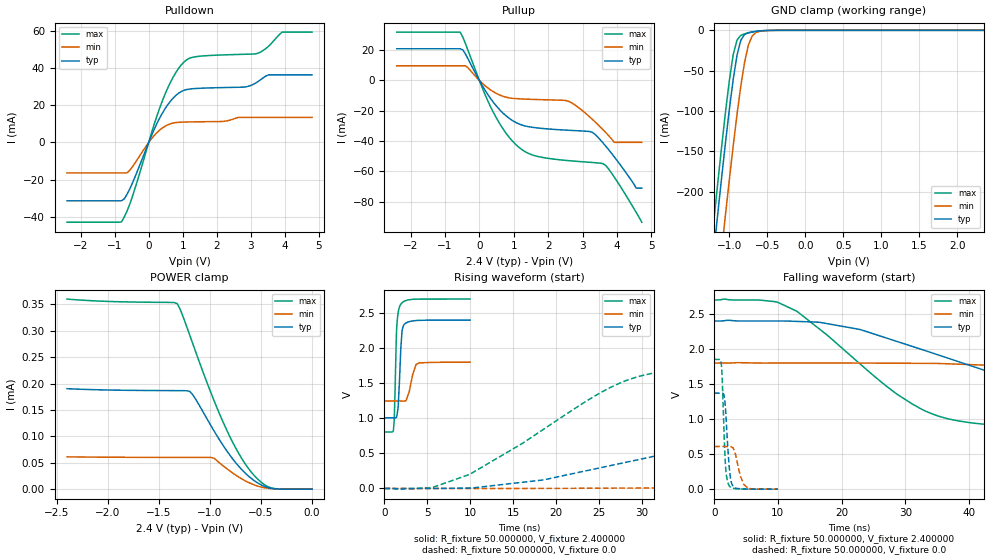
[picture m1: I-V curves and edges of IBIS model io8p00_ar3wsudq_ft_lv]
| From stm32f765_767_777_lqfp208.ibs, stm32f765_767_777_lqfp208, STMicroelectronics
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|   Model io8p00_ar3wsudq_ft_lv
[Model]  io8p00_ar3wsudq_ft_lv
Model_type I/O
Polarity   Non-Inverting
Enable   Active-Low
Vinl =   0.720000V
Vinh =   1.680000V
Vmeas =  1.200000V
Cref =   50.000000pF
Rref =   100.000000M
Vref =   0.0V
C_comp   3.740200pF   3.683500pF   3.822900pF
[Temperature Range]   25.000000   0.125000k   -40.000000
[Pullup Reference]   2.400000V   1.800000V   2.700000V
[Pulldown Reference]   0.0V   0.0V   0.0V
[POWER Clamp Reference]   2.400000V   1.800000V   2.700000V
[GND Clamp Reference]   0.0V   0.0V   0.0V
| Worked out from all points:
|   slope of the pulldown table from 0 to 0.36 V, typ, clamps not added: 25 ohm
|   slope of the pullup table from 0 to 0.36 V, typ, clamps not added: 27.7 ohm
|   GND clamp passes 1 mA (typ) near -0.62 V on its own axis
|   rising waveform, R_fixture 50.000000, V_fixture 2.400000: 20-80 % time 329ps typ, 643ps min, 256ps max; typ from 1.01 V to 2.4 V
|   rising waveform, R_fixture 50.000000, V_fixture 0.0: 20-80 % time 32.3ns typ, 81ns min, 14.8ns max; typ from 0 V to 1.37 V
|   falling waveform, R_fixture 50.000000, V_fixture 2.400000: 20-80 % time 29.1ns typ, 72.5ns min, 15.7ns max; typ from 2.4 V to 1.01 V
|   falling waveform, R_fixture 50.000000, V_fixture 0.0: 20-80 % time 594ps typ, 1.03ns min, 462ps max; typ from 1.37 V to 0 V
[Pulldown]
|Voltage   I(typ)   I(min)   I(max)
-2.4V     -31.47mA   -16.45mA   -43.01mA
-800mV    -31.47mA   -16.45mA   -42.85mA
-480mV    -21.98mA   -13.17mA   -29.21mA
80mV      3.63mA     1.966mA    5.014mA
480mV     18.16mA    8.738mA    26.02mA
800mV     25.38mA    10.72mA    37.77mA
1.12V     28.53mA    11.02mA    44.6mA
2.8V      29.84mA    13.51mA    47.53mA
3.2V      32.66mA    13.51mA    48.04mA
3.52V     36.44mA    13.51mA    51.84mA
3.92V     36.44mA    13.51mA    59.5mA
4.8V      36.44mA    13.51mA    59.5mA
[Pullup]
|Voltage   I(typ)   I(min)   I(max)
-2.4V     20.89mA    9.661mA    31.89mA
-560mV    20.89mA    9.661mA    31.89mA
-400mV    17.28mA    9.661mA    24.06mA
320mV     -11.75mA   -6.207mA   -17.08mA
960mV     -26.47mA   -11.82mA   -40.02mA
1.52V     -30.88mA   -12.51mA   -49.05mA
2.56V     -32.88mA   -13.52mA   -52.9mA
3.28V     -34.25mA   -25.63mA   -54.18mA
3.6V      -41.44mA   -32.74mA   -55.03mA
3.92V     -50.47mA   -40.9mA    -63.79mA
4.56V     -71.1mA    -40.9mA    -87.26mA
4.72V     -71.1mA    -40.9mA    -93.6mA
[GND_clamp]
|Voltage   I(typ)   I(min)   I(max)
-2.4V     -1.43A     -1.515A    -1.4A
-1.25V    -315.9mA   -407.2mA   -278.2mA
-1.2V     -270.1mA   -361.3mA   -232.1mA
-1.15V    -225mA     -316mA     -186.8mA
-1.1V     -180.9mA   -271.3mA   -142.7mA
-1.05V    -138.2mA   -227.5mA   -100.5mA
-950mV    -61.14mA   -143.6mA   -30.43mA
-900mV    -31.23mA   -104.7mA   -12.14mA
-850mV    -12.49mA   -69.4mA    -6.221mA
-750mV    -2.898mA   -18.35mA   -3.18mA
-600mV    -750.2uA   -1.218mA   -738.3uA
2.35V     0A         0A         0A
[POWER_clamp]
|Voltage   I(typ)   I(min)   I(max)
-2.4V     190.2uA    61.19uA    359.9uA
-1.32V    186.6uA    60.14uA    351.2uA
-1.29V    186.5uA    60.13uA    339.6uA
-1.2V     185.4uA    60.11uA    292.6uA
-1.17V    179.2uA    60.11uA    276.3uA
-960mV    110.2uA    58.62uA    167.5uA
-870mV    82.44uA    43.99uA    126.3uA
-750mV    50.58uA    26.92uA    78.64uA
-630mV    25.94uA    13.41uA    41.02uA
-510mV    9.22uA     4.527uA    14.97uA
-420mV    2.425uA    1.38uA     3.75uA
0V        0A         0A         0A
[Ramp]
| variable   typ   min   max
dV/dt_r  0.82206/32.24971n   0.36255/83.54246n   1.11078/14.74251n
dV/dt_f  0.83652/29.04373n   0.32640/73.61923n   1.13720/15.66467n
R_load = 50.000000
[Rising Waveform]
R_fixture= 50.000000
V_fixture= 2.400000
V_fixture_min= 1.800000
V_fixture_max= 2.700000
|time   V(typ)   V(min)   V(max)
0s        1.006V     1.247V     804.6mV
1.041ns   1.006V     1.247V     830.9mV
1.141ns   1.006V     1.247V     1.004V
1.421ns   1.019V     1.247V     2.284V
1.602ns   1.185V     1.247V     2.511V
1.882ns   1.947V     1.247V     2.624V
2.042ns   2.24V      1.246V     2.647V
2.182ns   2.315V     1.245V     2.66V
4.024ns   2.396V     1.79V      2.699V
9.97ns    2.4V       1.8V       2.7V
[Rising Waveform]
R_fixture= 50.000000
V_fixture= 0.0
V_fixture_min= 0.0
V_fixture_max= 0.0
|time   V(typ)   V(min)   V(max)
0s        6.447nV    361.2nV    2.755nV
5.506ns   -210.6uV   -120.4uV   13.13mV
9.51ns    5.653mV    -62.13uV   182.9mV
27.03ns   344.6mV    4.862mV    1.481V
32.53ns   492mV      9.434mV    1.676V
38.04ns   657.6mV    26.44mV    1.755V
64.06ns   1.222V     114.3mV    1.839V
79.08ns   1.313V     188.9mV    1.849V
148.1ns   1.368V     493mV      1.852V
249.2ns   1.37V      609.1mV    1.852V
[Falling Waveform]
R_fixture= 50.000000
V_fixture= 2.400000
V_fixture_min= 1.800000
V_fixture_max= 2.700000
|time   V(typ)   V(min)   V(max)
0s        2.4V       1.8V       2.7V
10.01ns   2.4V       1.8V       2.665V
13.01ns   2.394V     1.8V       2.536V
22.52ns   2.285V     1.8V       1.816V
31.53ns   2.024V     1.796V     1.192V
44.54ns   1.631V     1.763V     906.6mV
58.56ns   1.265V     1.718V     851.8mV
83.58ns   1.084V     1.58V      819.9mV
176.2ns   1.01V      1.276V     804.5mV
249.2ns   1.006V     1.247V     804.6mV
[Falling Waveform]
R_fixture= 50.000000
V_fixture= 0.0
V_fixture_min= 0.0
V_fixture_max= 0.0
|time   V(typ)   V(min)   V(max)
0s        1.37V      609.1mV    1.852V
1.141ns   1.37V      609.1mV    1.762V
1.722ns   1.207V     608.8mV    417.6mV
1.942ns   892.4mV    608.5mV    181.3mV
2.302ns   378.9mV    609.6mV    56.32mV
2.543ns   165.5mV    609.2mV    30.25mV
2.943ns   44.91mV    591.9mV    13.19mV
4.104ns   4.992mV    186.7mV    2.606mV
5.285ns   1.442mV    14.22mV    758.7uV
9.97ns    6.447nV    361.2nV    2.755nV
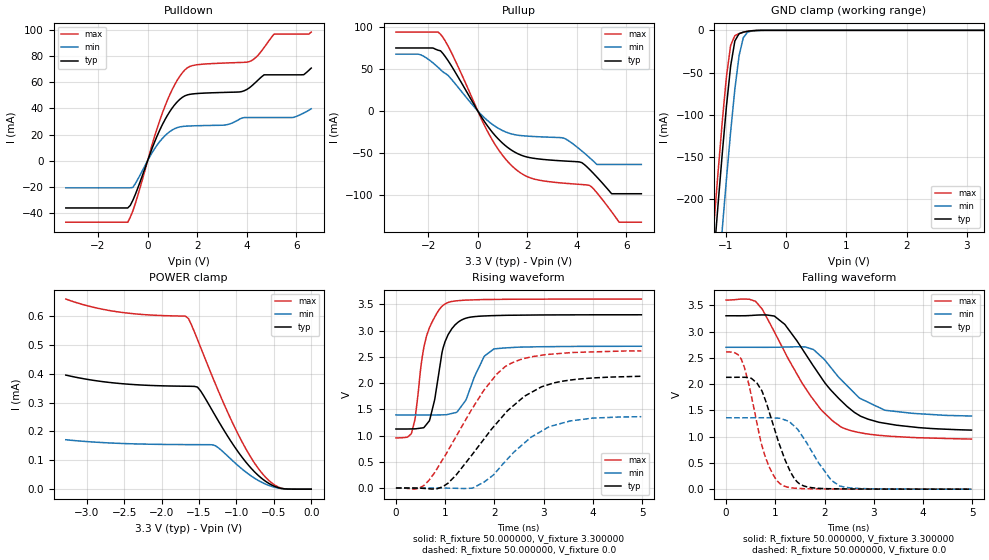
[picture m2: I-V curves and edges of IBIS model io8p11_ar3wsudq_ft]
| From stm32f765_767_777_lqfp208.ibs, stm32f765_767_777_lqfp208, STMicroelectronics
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|   Model io8p11_ar3wsudq_ft
[Model]  io8p11_ar3wsudq_ft
Model_type I/O
Polarity   Non-Inverting
Enable   Active-Low
Vinl =   0.990000V
Vinh =   2.310000V
Vmeas =  1.650000V
Cref =   30.000000pF
Rref =   100.000000M
Vref =   0.0V
C_comp   3.843200pF   3.761700pF   3.937000pF
[Temperature Range]   25.000000   0.125000k   -40.000000
[Pullup Reference]   3.300000V   2.700000V   3.600000V
[Pulldown Reference]   0.0V   0.0V   0.0V
[POWER Clamp Reference]   3.300000V   2.700000V   3.600000V
[GND Clamp Reference]   0.0V   0.0V   0.0V
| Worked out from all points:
|   slope of the pulldown table from 0 to 0.495 V, typ, clamps not added: 20.9 ohm
|   slope of the pullup table from 0 to 0.495 V, typ, clamps not added: 22.6 ohm
|   GND clamp passes 1 mA (typ) near -0.62 V on its own axis
|   rising waveform, R_fixture 50.000000, V_fixture 3.300000: 20-80 % time 279ps typ, 352ps min, 279ps max; typ from 1.12 V to 3.3 V
|   rising waveform, R_fixture 50.000000, V_fixture 0.0: 20-80 % time 1.18ns typ, 961ps min, 1.04ns max; typ from 0 V to 2.13 V
|   falling waveform, R_fixture 50.000000, V_fixture 3.300000: 20-80 % time 1.07ns typ, 865ps min, 1.02ns max; typ from 3.3 V to 1.12 V
|   falling waveform, R_fixture 50.000000, V_fixture 0.0: 20-80 % time 466ps typ, 565ps min, 398ps max; typ from 2.13 V to 0 V
[Pulldown]
|Voltage   I(typ)   I(min)   I(max)
-3.3V     -36.18mA   -20.77mA   -47.07mA
-800mV    -36.18mA   -20.77mA   -47.07mA
-600mV    -30.5mA    -20.52mA   -38.69mA
700mV     31.4mA     19.11mA    41.71mA
1.2V      45.15mA    25.37mA    61.75mA
1.6V      50.35mA    26.5mA     71.06mA
3.1V      52.28mA    27.26mA    74.76mA
4.1V      55.71mA    33.01mA    75.8mA
4.7V      65.73mA    33.01mA    86.69mA
5.1V      65.73mA    33.01mA    96.9mA
6.3V      65.85mA    36.5mA     96.9mA
6.6V      70.91mA    39.71mA    98.45mA
[Pullup]
|Voltage   I(typ)   I(min)   I(max)
-3.3V     74.74mA    67.41mA    93.61mA
-2.3V     74.74mA    66.57mA    93.61mA
-1.5V     71.37mA    49.01mA    91.04mA
500mV     -22.07mA   -14mA      -30.03mA
1.6V      -50.64mA   -28.81mA   -70.96mA
3.5V      -59.53mA   -32.72mA   -85.92mA
4.2V      -61.52mA   -47.62mA   -87.46mA
4.5V      -69.21mA   -55.27mA   -88.43mA
4.8V      -78.38mA   -63.6mA    -97.01mA
5.4V      -98.4mA    -63.6mA    -119.7mA
5.7V      -98.4mA    -63.6mA    -132.2mA
6.6V      -98.4mA    -63.6mA    -132.2mA
[GND_clamp]
|Voltage   I(typ)   I(min)   I(max)
-3.3V     -2.325A    -2.404A    -2.299A
-1.2V     -270.2mA   -361.4mA   -232.1mA
-1.13V    -207.3mA   -298.1mA   -169mA
-1.06V    -146.7mA   -236.2mA   -108.8mA
-990mV    -90.18mA   -176.4mA   -54.96mA
-920mV    -42.21mA   -120mA     -17.68mA
-850mV    -12.57mA   -69.47mA   -6.265mA
-780mV    -3.971mA   -30.01mA   -3.886mA
-710mV    -2.1mA     -8.615mA   -2.382mA
-640mV    -1.148mA   -2.283mA   -1.22mA
-570mV    -524uA     -821.5uA   -476.8uA
3.28V     0A         0A         0A
[POWER_clamp]
|Voltage   I(typ)   I(min)   I(max)
-3.28V    395.3uA    171.3uA    658.7uA
-2.6V     367.1uA    159uA      614.9uA
-1.68V    356.7uA    154.4uA    599.4uA
-1.64V    356.5uA    154.4uA    590.8uA
-1.52V    353.6uA    154.3uA    518.3uA
-1.48V    341.1uA    154.2uA    492.3uA
-1.28V    253.6uA    150.4uA    364.2uA
-960mV    123.1uA    77.56uA    181.6uA
-720mV    50.52uA    32.03uA    76.18uA
-560mV    18.94uA    12.27uA    28.65uA
-440mV    5.104uA    3.69uA     7.327uA
0V        0A         0A         0A
[Ramp]
| variable   typ   min   max
dV/dt_r  1.25880/1.16613n   0.80004/0.94614n   1.56012/1.04037n
dV/dt_f  1.27488/1.04977n   0.76812/0.84639n   1.56922/1.01475n
R_load = 50.000000
[Rising Waveform]
R_fixture= 50.000000
V_fixture= 3.300000
V_fixture_min= 2.700000
V_fixture_max= 3.600000
|time   V(typ)   V(min)   V(max)
0s        1.124V     1.392V     954.3mV
320.3ps   1.126V     1.392V     1.056V
390.4ps   1.127V     1.392V     1.324V
560.6ps   1.148V     1.392V     2.643V
680.7ps   1.281V     1.392V     3.052V
1.011ns   2.816V     1.395V     3.514V
1.421ns   3.235V     1.674V     3.579V
1.792ns   3.277V     2.505V     3.59V
1.992ns   3.284V     2.65V      3.592V
4.985ns   3.3V       2.7V       3.599V
[Rising Waveform]
R_fixture= 50.000000
V_fixture= 0.0
V_fixture_min= 0.0
V_fixture_max= 0.0
|time   V(typ)   V(min)   V(max)
0s        345.1uV    196.2uV    650.8uV
570.6ps   -7.291mV   186.7uV    49.81mV
1.061ns   94.14mV    -2.415mV   718.2mV
1.562ns   652.2mV    -576.7uV   1.531V
2.042ns   1.23V      314.7mV    2.163V
2.282ns   1.485V     568.7mV    2.348V
2.613ns   1.75V      860.9mV    2.468V
3.123ns   1.977V     1.172V     2.547V
3.994ns   2.096V     1.331V     2.593V
4.985ns   2.129V     1.359V     2.612V
[Falling Waveform]
R_fixture= 50.000000
V_fixture= 3.300000
V_fixture_min= 2.700000
V_fixture_max= 3.600000
|time   V(typ)   V(min)   V(max)
0s        3.3V       2.7V       3.599V
600.6ps   3.311V     2.7V       3.573V
740.7ps   3.316V     2.7V       3.416V
981ps     3.295V     2.701V     2.994V
1.201ns   3.126V     2.704V     2.594V
1.772ns   2.347V     2.659V     1.707V
2.342ns   1.678V     2.078V     1.18V
2.713ns   1.4V       1.732V     1.077V
3.223ns   1.255V     1.503V     1.015V
4.985ns   1.124V     1.392V     954.3mV
[Falling Waveform]
R_fixture= 50.000000
V_fixture= 0.0
V_fixture_min= 0.0
V_fixture_max= 0.0
|time   V(typ)   V(min)   V(max)
0s        2.129V     1.359V     2.612V
310.3ps   2.129V     1.359V     2.472V
470.5ps   2.117V     1.358V     1.966V
630.6ps   2.015V     1.358V     1.242V
880.9ps   1.457V     1.359V     415.9mV
1.131ns   729.4mV    1.338V     82.34mV
1.491ns   102.4mV    1.088V     13.53mV
2.132ns   8.311mV    175.9mV    3.479mV
2.312ns   5.515mV    59.99mV    3.074mV
4.985ns   345.1uV    196.2uV    650.8uV
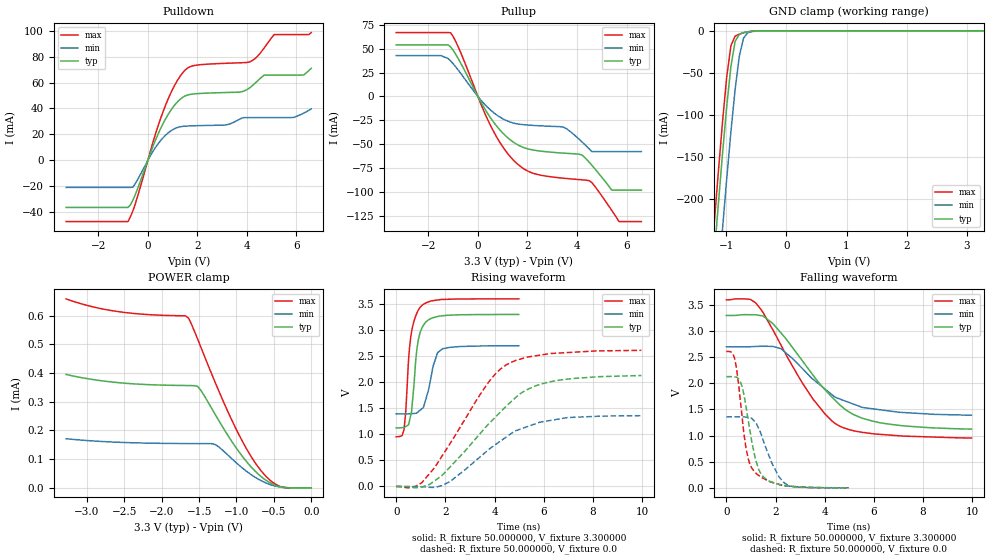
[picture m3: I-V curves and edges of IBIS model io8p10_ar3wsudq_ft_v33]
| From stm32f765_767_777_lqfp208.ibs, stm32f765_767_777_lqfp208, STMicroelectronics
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|   Model io8p10_ar3wsudq_ft_v33
[Model]  io8p10_ar3wsudq_ft_v33
Model_type I/O
Polarity   Non-Inverting
Enable   Active-Low
Vinl =   0.990000V
Vinh =   2.310000V
Vmeas =  1.650000V
Cref =   40.000000pF
Rref =   100.000000M
Vref =   0.0V
C_comp   3.857500pF   3.760500pF   3.941700pF
[Temperature Range]   25.000000   0.125000k   -40.000000
[Pullup Reference]   3.300000V   2.700000V   3.600000V
[Pulldown Reference]   0.0V   0.0V   0.0V
[POWER Clamp Reference]   3.300000V   2.700000V   3.600000V
[GND Clamp Reference]   0.0V   0.0V   0.0V
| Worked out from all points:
|   slope of the pulldown table from 0 to 0.495 V, typ, clamps not added: 20.9 ohm
|   slope of the pullup table from 0 to 0.495 V, typ, clamps not added: 22.6 ohm
|   GND clamp passes 1 mA (typ) near -0.62 V on its own axis
|   rising waveform, R_fixture 50.000000, V_fixture 3.300000: 20-80 % time 278ps typ, 400ps min, 275ps max; typ from 1.12 V to 3.3 V
|   rising waveform, R_fixture 50.000000, V_fixture 0.0: 20-80 % time 2.56ns typ, 2.3ns min, 2.13ns max; typ from 0 V to 2.13 V
|   falling waveform, R_fixture 50.000000, V_fixture 3.300000: 20-80 % time 2.28ns typ, 2.11ns min, 2.06ns max; typ from 3.3 V to 1.12 V
|   falling waveform, R_fixture 50.000000, V_fixture 0.0: 20-80 % time 516ps typ, 709ps min, 442ps max; typ from 2.13 V to 0 V
[Pulldown]
|Voltage   I(typ)   I(min)   I(max)
-3.3V     -36.18mA   -20.77mA   -47.07mA
-800mV    -36.18mA   -20.77mA   -47.07mA
-600mV    -30.5mA    -20.52mA   -38.69mA
700mV     31.4mA     19.11mA    41.71mA
1.2V      45.15mA    25.37mA    61.75mA
1.6V      50.35mA    26.5mA     71.06mA
3.1V      52.28mA    27.26mA    74.76mA
4.1V      55.7mA     32.99mA    75.8mA
4.7V      65.72mA    32.99mA    86.64mA
5.1V      65.72mA    32.99mA    96.89mA
6.3V      65.85mA    36.5mA     96.89mA
6.6V      70.91mA    39.71mA    98.45mA
[Pullup]
|Voltage   I(typ)   I(min)   I(max)
-3.3V     54.18mA    42.91mA    67.09mA
-1.5V     54.18mA    42.91mA    67.09mA
-1.1V     51.95mA    37.28mA    66.83mA
500mV     -22.07mA   -14mA      -30.03mA
1.5V      -49.1mA    -28.3mA    -68.56mA
2.2V      -56.05mA   -30.32mA   -80.35mA
3.5V      -59.53mA   -32.72mA   -85.92mA
4.2V      -61.52mA   -47.6mA    -87.46mA
4.5V      -69.21mA   -55.15mA   -88.43mA
5.4V      -98.3mA    -57.9mA    -119.4mA
5.7V      -98.3mA    -57.9mA    -131.3mA
6.6V      -98.3mA    -57.9mA    -131.3mA
[GND_clamp]
|Voltage   I(typ)   I(min)   I(max)
-3.3V     -2.333A    -2.407A    -2.313A
-1.2V     -270.2mA   -361.4mA   -232.1mA
-1.13V    -207.3mA   -298.1mA   -169mA
-1.06V    -146.7mA   -236.2mA   -108.8mA
-990mV    -90.18mA   -176.4mA   -54.96mA
-920mV    -42.21mA   -120mA     -17.68mA
-850mV    -12.57mA   -69.47mA   -6.265mA
-780mV    -3.971mA   -30.01mA   -3.886mA
-710mV    -2.1mA     -8.615mA   -2.382mA
-640mV    -1.148mA   -2.283mA   -1.22mA
-570mV    -524uA     -821.5uA   -476.8uA
3.28V     0A         0A         0A
[POWER_clamp]
|Voltage   I(typ)   I(min)   I(max)
-3.28V    395.3uA    171.3uA    658.7uA
-2.6V     367.1uA    159uA      614.9uA
-1.68V    356.7uA    154.4uA    599.4uA
-1.64V    356.5uA    154.4uA    590.8uA
-1.52V    353.6uA    154.3uA    518.3uA
-1.48V    341.1uA    154.2uA    492.3uA
-1.28V    253.6uA    150.4uA    364.2uA
-960mV    123.1uA    77.55uA    181.6uA
-720mV    50.52uA    32.03uA    76.18uA
-560mV    18.94uA    12.27uA    28.65uA
-440mV    5.104uA    3.69uA     7.327uA
0V        0A         0A         0A
[Ramp]
| variable   typ   min   max
dV/dt_r  1.26882/2.56042n   0.81306/2.31943n   1.56564/2.13181n
dV/dt_f  1.28502/2.27385n   0.77796/2.11306n   1.57580/2.05912n
R_load = 50.000000
[Rising Waveform]
R_fixture= 50.000000
V_fixture= 3.300000
V_fixture_min= 2.700000
V_fixture_max= 3.600000
|time   V(typ)   V(min)   V(max)
0s        1.124V     1.392V     954.2mV
320.3ps   1.132V     1.392V     1.098V
390.4ps   1.151V     1.391V     1.455V
510.5ps   1.199V     1.392V     2.477V
650.7ps   1.576V     1.398V     3.035V
830.8ps   2.593V     1.409V     3.315V
991ps     2.978V     1.471V     3.448V
1.682ns   3.26V      2.566V     3.577V
1.882ns   3.274V     2.641V     3.588V
4.985ns   3.3V       2.7V       3.599V
[Rising Waveform]
R_fixture= 50.000000
V_fixture= 0.0
V_fixture_min= 0.0
V_fixture_max= 0.0
|time   V(typ)   V(min)   V(max)
0s        195.9uV    83.64uV    715uV
560.6ps   -9.815mV   -61.16uV   -21.69mV
1.041ns   -6.999mV   -4.667mV   73.34mV
1.361ns   40.27mV    -15.48mV   251.4mV
2.182ns   370.7mV    92.42mV    818.2mV
3.804ns   1.221V     725.7mV    2.03V
4.505ns   1.555V     959.1mV    2.34V
5.145ns   1.811V     1.117V     2.457V
6.226ns   2.005V     1.264V     2.547V
9.97ns    2.129V     1.359V     2.612V
[Falling Waveform]
R_fixture= 50.000000
V_fixture= 3.300000
V_fixture_min= 2.700000
V_fixture_max= 3.600000
|time   V(typ)   V(min)   V(max)
0s        3.3V       2.7V       3.599V
961ps     3.315V     2.702V     3.609V
1.201ns   3.312V     2.707V     3.539V
1.502ns   3.286V     2.711V     3.35V
2.222ns   2.966V     2.664V     2.733V
3.524ns   2.16V      2.08V      1.7V
4.545ns   1.62V      1.713V     1.198V
5.165ns   1.404V     1.604V     1.094V
6.266ns   1.245V     1.494V     1.023V
9.97ns    1.124V     1.392V     954.2mV
[Falling Waveform]
R_fixture= 50.000000
V_fixture= 0.0
V_fixture_min= 0.0
V_fixture_max= 0.0
|time   V(typ)   V(min)   V(max)
0s        2.129V     1.359V     2.612V
340.3ps   2.126V     1.358V     2.474V
510.5ps   2.076V     1.358V     1.935V
650.7ps   1.926V     1.358V     1.317V
890.9ps   1.294V     1.347V     553.4mV
1.171ns   578.1mV    1.262V     295.8mV
1.542ns   194.7mV    853.3mV    173.3mV
2.132ns   66.22mV    218.4mV    67.9mV
2.422ns   40.07mV    73.36mV    36.71mV
4.985ns   195.9uV    83.64uV    715uV
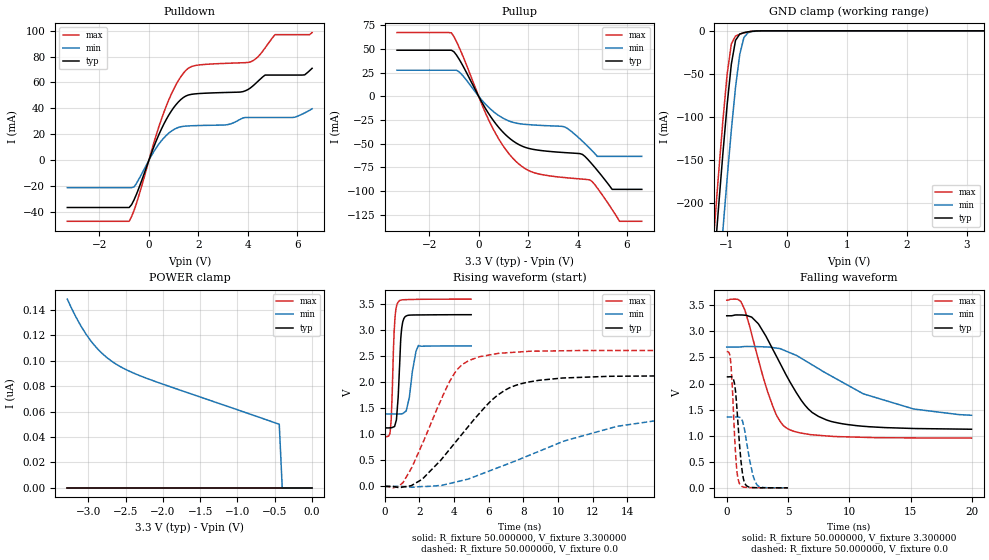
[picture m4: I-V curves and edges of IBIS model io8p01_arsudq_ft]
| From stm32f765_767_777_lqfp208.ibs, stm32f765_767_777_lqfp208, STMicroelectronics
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|   Model io8p01_arsudq_ft
[Model]  io8p01_arsudq_ft
Model_type I/O
Polarity   Non-Inverting
Enable   Active-Low
Vinl =   0.990000V
Vinh =   2.310000V
Vmeas =  1.650000V
Cref =   50.000000pF
Rref =   100.000000M
Vref =   0.0V
C_comp   2.292100pF   2.228000pF   2.366600pF
[Temperature Range]   25.000000   0.125000k   -40.000000
[Pullup Reference]   3.300000V   2.700000V   3.600000V
[Pulldown Reference]   0.0V   0.0V   0.0V
[POWER Clamp Reference]   3.300000V   2.700000V   3.600000V
[GND Clamp Reference]   0.0V   0.0V   0.0V
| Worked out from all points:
|   slope of the pulldown table from 0 to 0.495 V, typ, clamps not added: 20.9 ohm
|   slope of the pullup table from 0 to 0.495 V, typ, clamps not added: 22.6 ohm
|   GND clamp passes 1 mA (typ) near -0.62 V on its own axis
|   rising waveform, R_fixture 50.000000, V_fixture 3.300000: 20-80 % time 192ps typ, 339ps min, 165ps max; typ from 1.12 V to 3.3 V
|   rising waveform, R_fixture 50.000000, V_fixture 0.0: 20-80 % time 3.33ns typ, 6.83ns min, 2.09ns max; typ from 0 V to 2.13 V
|   falling waveform, R_fixture 50.000000, V_fixture 3.300000: 20-80 % time 3.18ns typ, 6.84ns min, 2ns max; typ from 3.3 V to 1.12 V
|   falling waveform, R_fixture 50.000000, V_fixture 0.0: 20-80 % time 434ps typ, 633ps min, 342ps max; typ from 2.13 V to 0 V
[Pulldown]
|Voltage   I(typ)   I(min)   I(max)
-3.3V     -36.46mA   -21.09mA   -47.09mA
-800mV    -36.46mA   -21.09mA   -47.09mA
-600mV    -30.5mA    -20.54mA   -38.69mA
700mV     31.4mA     19.11mA    41.71mA
1.2V      45.15mA    25.37mA    61.75mA
1.6V      50.35mA    26.5mA     71.06mA
3.1V      52.28mA    27.26mA    74.76mA
4.1V      55.7mA     33mA       75.81mA
4.7V      65.72mA    33mA       86.7mA
5.1V      65.72mA    33mA       96.91mA
6.3V      65.88mA    36.51mA    96.91mA
6.6V      70.94mA    39.72mA    98.51mA
[Pullup]
|Voltage   I(typ)   I(min)   I(max)
-3.3V     48.54mA    27.44mA    67.18mA
-1.1V     48.54mA    27.44mA    66.9mA
-700mV    35.13mA    23.47mA    46.35mA
500mV     -22.07mA   -14mA      -30.03mA
1.5V      -49.1mA    -28.3mA    -68.56mA
2.2V      -56.05mA   -30.32mA   -80.35mA
3.5V      -59.53mA   -32.65mA   -85.92mA
4.5V      -69.07mA   -55.12mA   -88.38mA
4.8V      -78.23mA   -63.5mA    -96.83mA
5.4V      -98.3mA    -63.5mA    -119.6mA
5.7V      -98.3mA    -63.5mA    -132mA
6.6V      -98.3mA    -63.5mA    -132mA
[GND_clamp]
|Voltage   I(typ)   I(min)   I(max)
-3.3V     -2.318A    -2.397A    -2.291A
-1.2V     -265.5mA   -356.1mA   -227.2mA
-1.13V    -202.6mA   -292.9mA   -164.1mA
-1.06V    -142.2mA   -231.2mA   -104.1mA
-990mV    -85.98mA   -171.6mA   -50.72mA
-920mV    -38.8mA    -115.5mA   -15.28mA
-850mV    -11.08mA   -65.6mA    -6.001mA
-780mV    -3.782mA   -27.42mA   -3.876mA
-710mV    -2.086mA   -7.69mA    -2.381mA
-640mV    -1.147mA   -2.118mA   -1.22mA
-570mV    -523.9uA   -798.4uA   -476.8uA
3.28V     0A         0A         0A
[POWER_clamp]
|Voltage   I(typ)   I(min)   I(max)
-3.28V    0A         148.5nA    0A
-3.2V     0A         138.6nA    0A
-3.12V    0A         129.7nA    0A
-3.04V    0A         122nA      0A
-2.96V    0A         115.3nA    0A
-2.8V     0A         105.1nA    0A
-2.6V     0A         96.44nA    0A
-2.4V     0A         90.52nA    0A
-2.16V    0A         84.97nA    0A
-440mV    0A         50.04nA    0A
-400mV    0A         0A         0A
0V        0A         0A         0A
[Ramp]
| variable   typ   min   max
dV/dt_r  1.27758/3.32597n   0.79926/6.83508n   1.56792/2.09053n
dV/dt_f  1.30236/3.17883n   0.74058/6.79960n   1.58788/1.99655n
R_load = 50.000000
[Rising Waveform]
R_fixture= 50.000000
V_fixture= 3.300000
V_fixture_min= 2.700000
V_fixture_max= 3.600000
|time   V(typ)   V(min)   V(max)
0s        1.124V     1.392V     954.3mV
300.3ps   1.126V     1.392V     1.015V
370.4ps   1.128V     1.392V     1.281V
500.5ps   1.142V     1.392V     2.637V
590.6ps   1.182V     1.392V     3.25V
760.8ps   1.666V     1.391V     3.537V
940.9ps   2.92V      1.394V     3.581V
1.161ns   3.257V     1.431V     3.588V
1.942ns   3.295V     2.708V     3.595V
4.985ns   3.3V       2.7V       3.599V
[Rising Waveform]
R_fixture= 50.000000
V_fixture= 0.0
V_fixture_min= 0.0
V_fixture_max= 0.0
|time   V(typ)   V(min)   V(max)
0s        358.2uV    205.4uV    684.6uV
1.081ns   -9.568mV   -1.992mV   89.31mV
2.162ns   138.3mV    -2.114mV   815.1mV
3.724ns   704.8mV    54.74mV    2.005V
4.244ns   917.6mV    95.92mV    2.268V
4.885ns   1.178V     150.8mV    2.423V
6.527ns   1.757V     359.7mV    2.555V
8.208ns   2V         580.5mV    2.594V
13.41ns   2.117V     1.155V     2.611V
19.94ns   2.129V     1.359V     2.612V
[Falling Waveform]
R_fixture= 50.000000
V_fixture= 3.300000
V_fixture_min= 2.700000
V_fixture_max= 3.600000
|time   V(typ)   V(min)   V(max)
0s        3.3V       2.7V       3.599V
880.9ps   3.315V     2.7V       3.615V
1.441ns   3.311V     2.71V      3.43V
2.563ns   3.15V      2.707V     2.473V
3.724ns   2.67V      2.691V     1.585V
4.965ns   2.111V     2.609V     1.135V
6.647ns   1.512V     2.403V     1.028V
8.488ns   1.275V     2.148V     989.3mV
15.22ns   1.138V     1.513V     958.1mV
19.94ns   1.124V     1.392V     954.3mV
[Falling Waveform]
R_fixture= 50.000000
V_fixture= 0.0
V_fixture_min= 0.0
V_fixture_max= 0.0
|time   V(typ)   V(min)   V(max)
0s        2.129V     1.359V     2.612V
300.3ps   2.13V      1.359V     2.474V
460.5ps   2.118V     1.358V     1.909V
620.6ps   2.016V     1.358V     1.085V
830.8ps   1.523V     1.36V      321.9mV
1.041ns   831.9mV    1.353V     81.21mV
1.451ns   101.9mV    1.118V     12.08mV
1.872ns   12.55mV    524.3mV    5.149mV
2.422ns   3.446mV    72.69mV    2.8mV
4.985ns   358.2uV    205.4uV    684.6uV
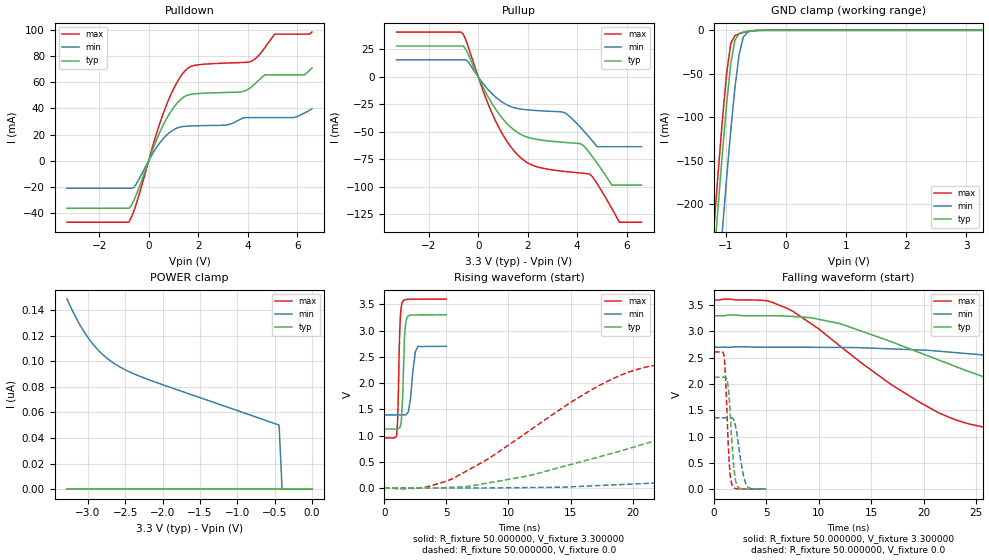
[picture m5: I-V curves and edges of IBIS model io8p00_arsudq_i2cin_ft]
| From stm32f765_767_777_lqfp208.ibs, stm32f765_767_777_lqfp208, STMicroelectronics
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|   Model io8p00_arsudq_i2cin_ft
[Model]  io8p00_arsudq_i2cin_ft
Model_type I/O
Polarity   Non-Inverting
Enable   Active-Low
Vinl =   0.990000V
Vinh =   2.310000V
Vmeas =  1.650000V
Cref =   50.000000pF
Rref =   100.000000M
Vref =   0.0V
C_comp   2.280000pF   2.217000pF   2.355700pF
[Temperature Range]   25.000000   0.125000k   -40.000000
[Pullup Reference]   3.300000V   2.700000V   3.600000V
[Pulldown Reference]   0.0V   0.0V   0.0V
[POWER Clamp Reference]   3.300000V   2.700000V   3.600000V
[GND Clamp Reference]   0.0V   0.0V   0.0V
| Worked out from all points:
|   slope of the pulldown table from 0 to 0.495 V, typ, clamps not added: 20.9 ohm
|   slope of the pullup table from 0 to 0.495 V, typ, clamps not added: 22.6 ohm
|   GND clamp passes 1 mA (typ) near -0.62 V on its own axis
|   rising waveform, R_fixture 50.000000, V_fixture 3.300000: 20-80 % time 190ps typ, 340ps min, 164ps max; typ from 1.12 V to 3.3 V
|   rising waveform, R_fixture 50.000000, V_fixture 0.0: 20-80 % time 19.7ns typ, 51ns min, 10.4ns max; typ from 0 V to 2.13 V
|   falling waveform, R_fixture 50.000000, V_fixture 3.300000: 20-80 % time 18.5ns typ, 39.1ns min, 11.3ns max; typ from 3.3 V to 1.12 V
|   falling waveform, R_fixture 50.000000, V_fixture 0.0: 20-80 % time 434ps typ, 633ps min, 343ps max; typ from 2.13 V to 0 V
[Pulldown]
|Voltage   I(typ)   I(min)   I(max)
-3.3V     -36.46mA   -21.09mA   -47.09mA
-800mV    -36.46mA   -21.09mA   -47.09mA
-600mV    -30.5mA    -20.54mA   -38.69mA
700mV     31.4mA     19.11mA    41.71mA
1.2V      45.15mA    25.37mA    61.75mA
1.6V      50.35mA    26.5mA     71.06mA
3.1V      52.28mA    27.26mA    74.76mA
4.1V      55.7mA     32.99mA    75.81mA
4.7V      65.72mA    32.99mA    86.7mA
5.1V      65.72mA    32.99mA    96.91mA
6.3V      65.88mA    36.51mA    96.91mA
6.6V      70.94mA    39.72mA    98.51mA
[Pullup]
|Voltage   I(typ)   I(min)   I(max)
-3.3V     28.04mA    15.43mA    40.69mA
-700mV    28.04mA    15.43mA    40.69mA
-400mV    20.31mA    13.47mA    26.93mA
600mV     -25.77mA   -16.23mA   -35.14mA
1.6V      -50.64mA   -28.81mA   -70.96mA
3.5V      -59.53mA   -32.65mA   -85.92mA
4.2V      -61.43mA   -47.48mA   -87.46mA
4.5V      -69.07mA   -55.13mA   -88.38mA
4.8V      -78.22mA   -63.4mA    -96.83mA
5.4V      -98.3mA    -63.4mA    -119.6mA
5.7V      -98.3mA    -63.4mA    -132mA
6.6V      -98.3mA    -63.4mA    -132mA
[GND_clamp]
|Voltage   I(typ)   I(min)   I(max)
-3.3V     -2.32A     -2.398A    -2.293A
-1.2V     -265.5mA   -356.1mA   -227.2mA
-1.13V    -202.6mA   -292.9mA   -164.1mA
-1.06V    -142.2mA   -231.2mA   -104.1mA
-990mV    -85.98mA   -171.6mA   -50.72mA
-920mV    -38.8mA    -115.5mA   -15.28mA
-850mV    -11.08mA   -65.6mA    -6.001mA
-780mV    -3.782mA   -27.42mA   -3.876mA
-710mV    -2.086mA   -7.69mA    -2.381mA
-640mV    -1.147mA   -2.118mA   -1.22mA
-570mV    -523.9uA   -798.4uA   -476.8uA
3.28V     0A         0A         0A
[POWER_clamp]
|Voltage   I(typ)   I(min)   I(max)
-3.28V    0A         148.5nA    0A
-3.2V     0A         138.6nA    0A
-3.12V    0A         129.7nA    0A
-3.04V    0A         122nA      0A
-2.96V    0A         115.3nA    0A
-2.8V     0A         105.1nA    0A
-2.6V     0A         96.44nA    0A
-2.4V     0A         90.52nA    0A
-2.16V    0A         84.97nA    0A
-440mV    0A         50.04nA    0A
-400mV    0A         0A         0A
0V        0A         0A         0A
[Ramp]
| variable   typ   min   max
dV/dt_r  1.27746/19.69570n   0.81552/50.99517n   1.56732/10.33277n
dV/dt_f  1.30608/18.50723n   0.78450/39.14537n   1.58789/11.31316n
R_load = 50.000000
[Rising Waveform]
R_fixture= 50.000000
V_fixture= 3.300000
V_fixture_min= 2.700000
V_fixture_max= 3.600000
|time   V(typ)   V(min)   V(max)
0s        1.124V     1.392V     953.5mV
1.001ns   1.126V     1.392V     1.026V
1.071ns   1.128V     1.392V     1.307V
1.291ns   1.184V     1.392V     3.266V
1.461ns   1.669V     1.391V     3.544V
1.632ns   2.892V     1.394V     3.586V
1.852ns   3.255V     1.429V     3.594V
2.503ns   3.297V     2.6V       3.598V
2.713ns   3.297V     2.701V     3.598V
4.985ns   3.3V       2.7V       3.6V
[Rising Waveform]
R_fixture= 50.000000
V_fixture= 0.0
V_fixture_min= 0.0
V_fixture_max= 0.0
|time   V(typ)   V(min)   V(max)
0s        11.18nV    250.1nV    19.51nV
5.506ns   13.86mV    -135.9uV   177mV
11.51ns   227.6mV    8.061mV    1.063V
19.52ns   739mV      70.27mV    2.194V
30.53ns   1.488V     217.9mV    2.533V
38.54ns   1.857V     360.1mV    2.58V
50.05ns   2.028V     569.2mV    2.601V
88.59ns   2.12V      1.135V     2.612V
116.6ns   2.129V     1.296V     2.612V
249.2ns   2.129V     1.359V     2.612V
[Falling Waveform]
R_fixture= 50.000000
V_fixture= 3.300000
V_fixture_min= 2.700000
V_fixture_max= 3.600000
|time   V(typ)   V(min)   V(max)
0s        3.3V       2.7V       3.6V
5.506ns   3.299V     2.7V       3.561V
12.01ns   3.15V      2.696V     2.725V
22.02ns   2.414V     2.615V     1.403V
30.53ns   1.791V     2.458V     1.081V
38.04ns   1.429V     2.277V     1.023V
46.05ns   1.28V      2.079V     995.3mV
62.56ns   1.184V     1.74V      969.4mV
86.09ns   1.145V     1.529V     957.2mV
249.2ns   1.124V     1.392V     953.5mV
[Falling Waveform]
R_fixture= 50.000000
V_fixture= 0.0
V_fixture_min= 0.0
V_fixture_max= 0.0
|time   V(typ)   V(min)   V(max)
0s        2.129V     1.359V     2.612V
981ps     2.13V      1.359V     2.506V
1.151ns   2.12V      1.358V     1.943V
1.411ns   1.866V     1.359V     683.5mV
1.542ns   1.483V     1.361V     296mV
1.742ns   825.7mV    1.354V     77.45mV
2.152ns   99.29mV    1.116V     7.157mV
2.823ns   3.671mV    252.8mV    1.393mV
3.123ns   1.658mV    71.85mV    1.038mV
4.985ns   11.18nV    250.1nV    19.51nV
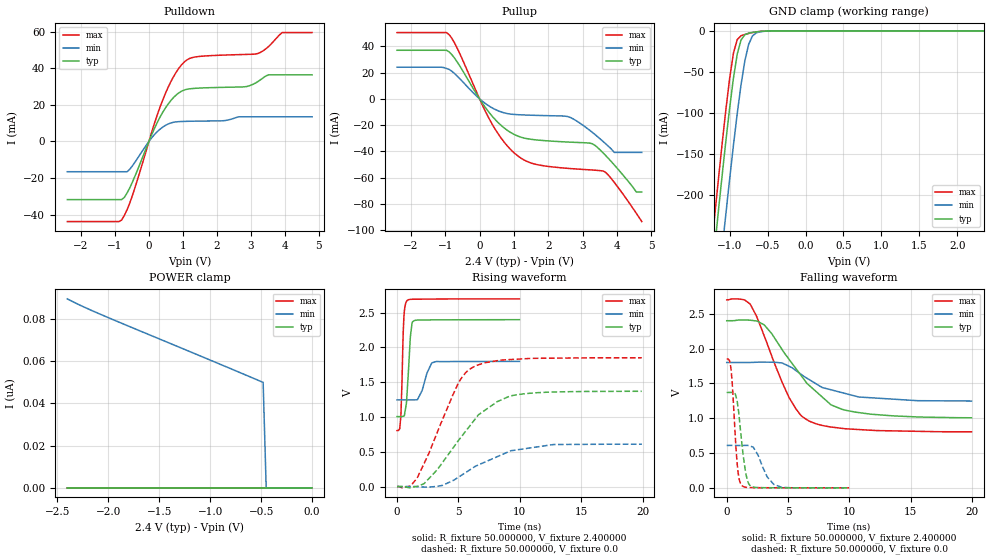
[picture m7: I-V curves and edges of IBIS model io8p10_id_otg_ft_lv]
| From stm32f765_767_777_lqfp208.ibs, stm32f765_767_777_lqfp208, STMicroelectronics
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|   Model io8p10_id_otg_ft_lv
[Model]  io8p10_id_otg_ft_lv
Model_type I/O
Polarity   Non-Inverting
Enable   Active-Low
Vinl =   0.720000V
Vinh =   1.680000V
Vmeas =  1.200000V
Cref =   40.000000pF
Rref =   100.000000M
Vref =   0.0V
C_comp   2.229800pF   2.169700pF   2.325100pF
[Temperature Range]   25.000000   0.125000k   -40.000000
[Pullup Reference]   2.400000V   1.800000V   2.700000V
[Pulldown Reference]   0.0V   0.0V   0.0V
[POWER Clamp Reference]   2.400000V   1.800000V   2.700000V
[GND Clamp Reference]   0.0V   0.0V   0.0V
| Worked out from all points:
|   slope of the pulldown table from 0 to 0.36 V, typ, clamps not added: 25 ohm
|   slope of the pullup table from 0 to 0.36 V, typ, clamps not added: 27.7 ohm
|   GND clamp passes 1 mA (typ) near -0.62 V on its own axis
|   rising waveform, R_fixture 50.000000, V_fixture 2.400000: 20-80 % time 277ps typ, 616ps min, 183ps max; typ from 1.01 V to 2.4 V
|   rising waveform, R_fixture 50.000000, V_fixture 0.0: 20-80 % time 3.74ns typ, 4.02ns min, 2.67ns max; typ from 0 V to 1.37 V
|   falling waveform, R_fixture 50.000000, V_fixture 2.400000: 20-80 % time 3.89ns typ, 4.01ns min, 2.72ns max; typ from 2.4 V to 1.01 V
|   falling waveform, R_fixture 50.000000, V_fixture 0.0: 20-80 % time 530ps typ, 979ps min, 384ps max; typ from 1.37 V to 0 V
[Pulldown]
|Voltage   I(typ)   I(min)   I(max)
-2.4V     -31.73mA   -16.51mA   -43.74mA
-800mV    -31.73mA   -16.51mA   -42.87mA
-480mV    -21.98mA   -13.17mA   -29.21mA
80mV      3.63mA     1.966mA    5.014mA
480mV     18.16mA    8.738mA    26.02mA
800mV     25.38mA    10.72mA    37.77mA
1.12V     28.53mA    11.02mA    44.6mA
2.8V      29.84mA    13.49mA    47.53mA
3.2V      32.65mA    13.49mA    48.05mA
3.52V     36.43mA    13.49mA    51.84mA
3.92V     36.43mA    13.49mA    59.49mA
4.8V      36.43mA    13.49mA    59.49mA
[Pullup]
|Voltage   I(typ)   I(min)   I(max)
-2.4V     36.91mA    24.04mA    50.37mA
-960mV    36.91mA    23.05mA    50.37mA
-640mV    27.65mA    17.03mA    38mA
320mV     -11.75mA   -6.207mA   -17.08mA
960mV     -26.47mA   -11.82mA   -40.02mA
1.52V     -30.88mA   -12.51mA   -49.05mA
2.56V     -32.88mA   -13.48mA   -52.9mA
3.28V     -34.19mA   -25.52mA   -54.18mA
3.6V      -41.31mA   -32.62mA   -54.97mA
3.92V     -50.32mA   -40.8mA    -63.63mA
4.56V     -70.9mA    -40.8mA    -87.08mA
4.72V     -70.9mA    -40.8mA    -93.4mA
[GND_clamp]
|Voltage   I(typ)   I(min)   I(max)
-2.4V     -1.424A    -1.508A    -1.393A
-1.25V    -311.2mA   -401.9mA   -273.3mA
-1.2V     -265.4mA   -356.1mA   -227.2mA
-1.15V    -220.4mA   -310.8mA   -181.9mA
-1.1V     -176.3mA   -266.2mA   -137.9mA
-1.05V    -133.8mA   -222.5mA   -95.88mA
-950mV    -57.31mA   -138.9mA   -26.99mA
-900mV    -28.28mA   -100.4mA   -10.61mA
-850mV    -11.02mA   -65.55mA   -5.978mA
-750mV    -2.847mA   -16.51mA   -3.192mA
-600mV    -755.4uA   -1.17mA    -743.6uA
2.35V     0A         0A         0A
[POWER_clamp]
|Voltage   I(typ)   I(min)   I(max)
-2.4V     0A         89.62nA    0A
-2.04V    0A         81.58nA    0A
-480mV    0A         50.01nA    0A
-450mV    0A         0A         0A
0V        0A         0A         0A
[Ramp]
| variable   typ   min   max
dV/dt_r  0.82206/3.73866n   0.36598/4.02342n   1.11420/2.67396n
dV/dt_f  0.83358/3.89622n   0.33234/4.06523n   1.13659/2.72205n
R_load = 50.000000
[Rising Waveform]
R_fixture= 50.000000
V_fixture= 2.400000
V_fixture_min= 1.800000
V_fixture_max= 2.700000
|time   V(typ)   V(min)   V(max)
0s        1.006V     1.247V     804.6mV
220.2ps   1.006V     1.247V     831.2mV
300.3ps   1.006V     1.247V     989.6mV
560.6ps   1.015V     1.247V     2.437V
820.8ps   1.347V     1.247V     2.674V
1.081ns   2.138V     1.247V     2.692V
1.341ns   2.381V     1.245V     2.694V
2.042ns   2.396V     1.38V      2.695V
2.843ns   2.397V     1.779V     2.697V
9.97ns    2.4V       1.8V       2.699V
[Rising Waveform]
R_fixture= 50.000000
V_fixture= 0.0
V_fixture_min= 0.0
V_fixture_max= 0.0
|time   V(typ)   V(min)   V(max)
0s        168.7uV    66.32uV    586.2uV
1.121ns   -14.76mV   125.1uV    12.35mV
1.642ns   512.4uV    -515.7uV   122.1mV
3.283ns   242.6mV    2.454mV    780.3mV
5.005ns   662.9mV    134.6mV    1.491V
6.206ns   934.8mV    271.3mV    1.718V
8.168ns   1.221V     429.8mV    1.811V
9.53ns    1.313V     521.6mV    1.829V
12.77ns   1.36V      604.1mV    1.847V
19.94ns   1.37V      609mV      1.851V
[Falling Waveform]
R_fixture= 50.000000
V_fixture= 2.400000
V_fixture_min= 1.800000
V_fixture_max= 2.700000
|time   V(typ)   V(min)   V(max)
0s        2.4V       1.8V       2.699V
1.441ns   2.41V      1.8V       2.7V
1.922ns   2.407V     1.801V     2.635V
3.043ns   2.341V     1.805V     2.187V
5.085ns   1.844V     1.745V     1.294V
6.046ns   1.616V     1.632V     1.04V
6.767ns   1.463V     1.549V     955mV
8.488ns   1.193V     1.408V     873.4mV
9.77ns    1.111V     1.35V      847.4mV
19.94ns   1.006V     1.247V     804.6mV
[Falling Waveform]
R_fixture= 50.000000
V_fixture= 0.0
V_fixture_min= 0.0
V_fixture_max= 0.0
|time   V(typ)   V(min)   V(max)
0s        1.37V      609mV      1.851V
340.3ps   1.37V      609mV      1.721V
440.4ps   1.37V      609mV      1.523V
700.7ps   1.346V     608.9mV    731mV
940.9ps   1.127V     608.7mV    201.8mV
1.241ns   625.7mV    608.5mV    33.3mV
1.682ns   106.8mV    610.3mV    5.892mV
2.042ns   18.13mV    591.4mV    3.27mV
3.844ns   1.302mV    48.81mV    1.423mV
9.97ns    168.7uV    66.32uV    586.2uV
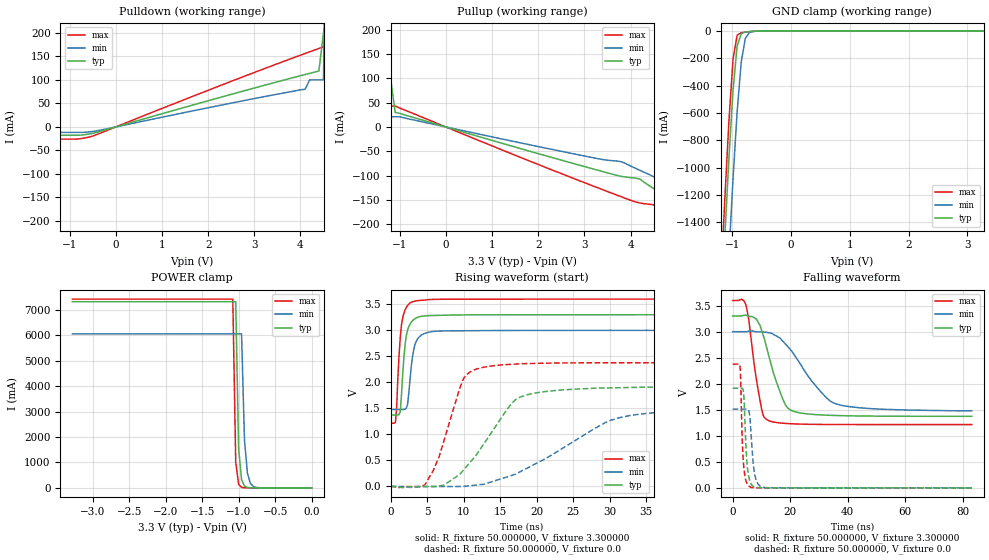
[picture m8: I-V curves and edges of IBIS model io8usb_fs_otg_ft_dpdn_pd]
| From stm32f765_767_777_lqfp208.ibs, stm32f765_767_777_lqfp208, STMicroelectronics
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|   Model io8usb_fs_otg_ft_dpdn_pd
[Model]  io8usb_fs_otg_ft_dpdn_pd
Model_type I/O
Polarity   Non-Inverting
Enable   Active-Low
Vinl =   0.990000V
Vinh =   2.310000V
Vmeas =  1.650000V
Cref =   50.000000pF
Rref =   100.000000M
Vref =   0.0V
C_comp   8.255900pF   7.991100pF   8.650600pF
[Temperature Range]   25.000000   0.125000k   -40.000000
[Pullup Reference]   3.300000V   3.000000V   3.600000V
[Pulldown Reference]   0.0V   0.0V   0.0V
[POWER Clamp Reference]   3.300000V   3.000000V   3.600000V
[GND Clamp Reference]   0.0V   0.0V   0.0V
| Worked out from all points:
|   slope of the pulldown table from 0 to 0.495 V, typ, clamps not added: 35.5 ohm
|   slope of the pullup table from 0 to 0.495 V, typ, clamps not added: 36 ohm
|   GND clamp passes 1 mA (typ) near -0.52 V on its own axis
|   POWER clamp passes 1 mA (typ) near -0.81 V on its own axis
|   rising waveform, R_fixture 50.000000, V_fixture 3.300000: 20-80 % time 690ps typ, 798ps min, 630ps max; typ from 1.37 V to 3.3 V
|   rising waveform, R_fixture 50.000000, V_fixture 0.0: 20-80 % time 5.83ns typ, 11.2ns min, 3.17ns max; typ from 0 V to 1.91 V
|   falling waveform, R_fixture 50.000000, V_fixture 3.300000: 20-80 % time 6.34ns typ, 12.3ns min, 3.62ns max; typ from 3.3 V to 1.37 V
|   falling waveform, R_fixture 50.000000, V_fixture 0.0: 20-80 % time 1.06ns typ, 1.33ns min, 891ps max; typ from 1.91 V to 0 V
[Pulldown]
|Voltage   I(typ)   I(min)   I(max)
-3.3V     -181mA     -11.57mA   -221mA
-3.2V     -137mA     -11.57mA   -216mA
-2.9V     -123mA     -11.57mA   -200mA
-2.8V     -17.71mA   -11.57mA   -25.94mA
-600mV    -15.43mA   -10.84mA   -22.06mA
4.1V      111.4mA    80mA       156.1mA
4.4V      119mA      100mA      166.8mA
4.5V      200mA      100mA      170.3mA
4.6V      200mA      1A         173.8mA
4.8V      1A         1A         200mA
5.4V      1A         1A         1A
6.6V      1A         1A         1A
[Pullup]
|Voltage   I(typ)   I(min)   I(max)
-3.3V     1A         1A         1A
-1.9V     1A         1A         1A
-1.8V     100mA      1A         1A
-1.7V     100mA      1A         100mA
-1.6V     100mA      1A         100mA
-1.5V     100mA      21mA       100mA
-1.3V     100mA      21mA       100mA
-1.2V     100mA      21mA       43mA
-1.1V     30mA       21mA       43mA
4.2V      -107.2mA   -89.2mA    -156.4mA
5V        -156.9mA   -125mA     -203.4mA
6.6V      -223mA     -162mA     -322mA
[GND_clamp]
|Voltage   I(typ)   I(min)   I(max)
-3.3V     -9.433A    -9.435A    -9.911A
-1.2V     -2.116A    -2.846A    -1.847A
-1.13V    -1.505A    -2.23A     -1.23A
-1.06V    -930.4mA   -1.637A    -658.9mA
-990mV    -432.7mA   -1.08A     -207.3mA
-920mV    -110.5mA   -590.3mA   -31.59mA
-850mV    -19.84mA   -226.8mA   -13.66mA
-780mV    -8.32mA    -54.05mA   -9.517mA
-710mV    -5.29mA    -11.97mA   -6.272mA
-640mV    -3.236mA   -4.296mA   -3.585mA
3.28V     149.6uA    102.1uA    206.8uA
[POWER_clamp]
|Voltage   I(typ)   I(min)   I(max)
-3.28V    7.328A     6.064A     7.43A
-1.08V    7.328A     6.064A     7.43A
-1.04V    7.328A     6.064A     1.015A
-1V       1.545A     6.064A     138.6mA
-960mV    325.6mA    6.064A     18.93mA
-920mV    68.64mA    1.89A      2.585mA
-880mV    14.47mA    589mA      353uA
-840mV    3.05mA     183.6mA    48.21uA
-800mV    642.9uA    57.21mA    6.589uA
-720mV    28.59uA    5.557mA    126.6nA
0V        0A         0A         0A
[Ramp]
| variable   typ   min   max
dV/dt_r  1.14777/5.82655n   0.90673/11.15371n   1.42544/3.16221n
dV/dt_f  1.15500/6.33272n   0.91014/12.25380n   1.43016/3.61621n
R_load = 50.000000
[Rising Waveform]
R_fixture= 50.000000
V_fixture= 3.300000
V_fixture_min= 3.000000
V_fixture_max= 3.600000
|time   V(typ)   V(min)   V(max)
0s        1.374V     1.479V     1.215V
667.3ps   1.374V     1.479V     1.234V
1.335ns   1.443V     1.479V     2.878V
1.668ns   2.177V     1.479V     3.244V
2.002ns   2.745V     1.484V     3.399V
2.336ns   3.008V     1.587V     3.478V
3.003ns   3.184V     2.494V     3.547V
3.504ns   3.237V     2.783V     3.565V
7.841ns   3.291V     2.989V     3.597V
83.08ns   3.299V     2.999V     3.599V
[Rising Waveform]
R_fixture= 50.000000
V_fixture= 0.0
V_fixture_min= 0.0
V_fixture_max= 0.0
|time   V(typ)   V(min)   V(max)
0s        158.5uV    83.44uV    305.8uV
4.671ns   -1.873mV   -1.475mV   29.32mV
6.673ns   11.07mV    -677uV     582.7mV
10.01ns   319.1mV    926.4uV    2.074V
12.68ns   798.6mV    41.07mV    2.288V
16.35ns   1.552V     201.3mV    2.345V
17.85ns   1.721V     290.1mV    2.357V
29.36ns   1.892V     1.223V     2.376V
32.7ns    1.901V     1.361V     2.376V
83.08ns   1.913V     1.511V     2.376V
[Falling Waveform]
R_fixture= 50.000000
V_fixture= 3.300000
V_fixture_min= 3.000000
V_fixture_max= 3.600000
|time   V(typ)   V(min)   V(max)
0s        3.299V     2.999V     3.599V
4.671ns   3.316V     2.999V     3.502V
8.175ns   3.243V     2.998V     2.108V
9.843ns   3.063V     2.995V     1.577V
12.18ns   2.615V     2.982V     1.3V
17.68ns   1.671V     2.802V     1.24V
21.52ns   1.464V     2.544V     1.228V
29.7ns    1.404V     1.905V     1.219V
36.2ns    1.39V      1.608V     1.216V
83.08ns   1.374V     1.479V     1.215V
[Falling Waveform]
R_fixture= 50.000000
V_fixture= 0.0
V_fixture_min= 0.0
V_fixture_max= 0.0
|time   V(typ)   V(min)   V(max)
0s        1.913V     1.511V     2.376V
2.503ns   1.913V     1.511V     2.348V
2.669ns   1.913V     1.511V     2.257V
3.67ns    1.875V     1.511V     536.3mV
5.005ns   462.3mV    1.512V     79.85mV
5.839ns   156.3mV    1.425V     25.77mV
6.34ns    85.06mV    1.076V     9.564mV
7.674ns   14.19mV    256.1mV    2.814mV
9.843ns   2.696mV    20.21mV    894.9uV
83.08ns   158.5uV    83.44uV    305.8uV
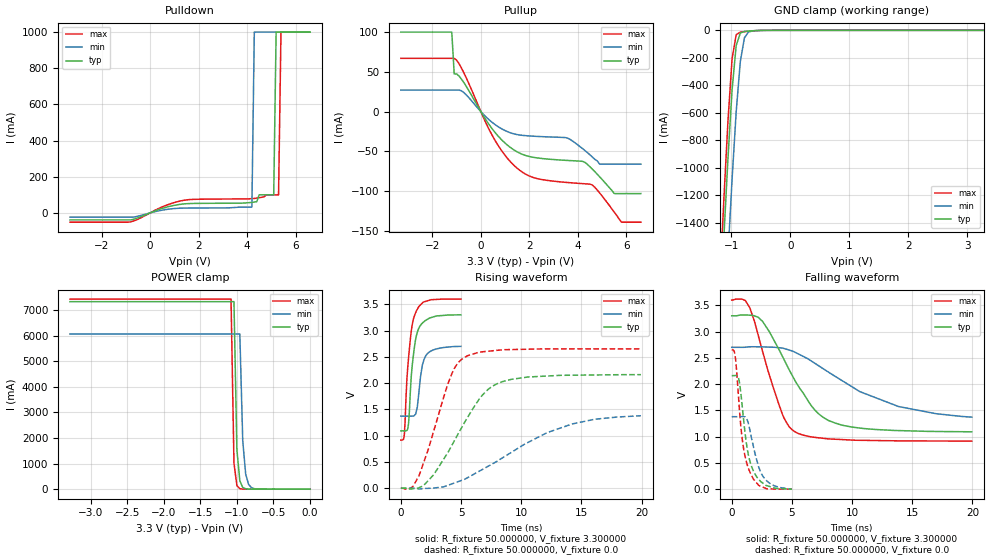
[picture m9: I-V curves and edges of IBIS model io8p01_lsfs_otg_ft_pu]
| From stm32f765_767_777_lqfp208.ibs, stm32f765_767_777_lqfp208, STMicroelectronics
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|   Model io8p01_lsfs_otg_ft_pu
[Model]  io8p01_lsfs_otg_ft_pu
Model_type I/O
Polarity   Non-Inverting
Enable   Active-Low
Vinl =   0.990000V
Vinh =   2.310000V
Vmeas =  1.650000V
Cref =   50.000000pF
Rref =   100.000000M
Vref =   0.0V
C_comp   8.196500pF   7.968500pF   8.492600pF
[Temperature Range]   25.000000   0.125000k   -40.000000
[Pullup Reference]   3.300000V   2.700000V   3.600000V
[Pulldown Reference]   0.0V   0.0V   0.0V
[POWER Clamp Reference]   3.300000V   2.700000V   3.600000V
[GND Clamp Reference]   0.0V   0.0V   0.0V
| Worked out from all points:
|   slope of the pulldown table from 0 to 0.495 V, typ, clamps not added: 20.1 ohm
|   slope of the pullup table from 0 to 0.495 V, typ, clamps not added: 21.8 ohm
|   GND clamp passes 1 mA (typ) near -0.52 V on its own axis
|   POWER clamp passes 1 mA (typ) near -0.80 V on its own axis
|   rising waveform, R_fixture 50.000000, V_fixture 3.300000: 20-80 % time 526ps typ, 492ps min, 529ps max; typ from 1.09 V to 3.3 V
|   rising waveform, R_fixture 50.000000, V_fixture 0.0: 20-80 % time 3.4ns typ, 6.59ns min, 2.18ns max; typ from 0.001 V to 2.16 V
|   falling waveform, R_fixture 50.000000, V_fixture 3.300000: 20-80 % time 3.36ns typ, 6.48ns min, 2.13ns max; typ from 3.3 V to 1.09 V
|   falling waveform, R_fixture 50.000000, V_fixture 0.0: 20-80 % time 847ps typ, 985ps min, 758ps max; typ from 2.16 V to 0.001 V
[Pulldown]
|Voltage   I(typ)   I(min)   I(max)
-3.3V     -38.65mA   -23.43mA   -51.3mA
-900mV    -38.65mA   -23.43mA   -51.3mA
1.4V      49.88mA    26.66mA    69.84mA
4.2V      58.43mA    32mA       78.86mA
4.3V      60.2mA     1A         80.13mA
4.4V      62mA       1A         81.72mA
4.5V      100mA      1A         83.79mA
5.1V      100mA      1A         100mA
5.2V      1A         1A         100mA
5.3V      1A         1A         100mA
5.4V      1A         1A         1A
6.6V      1A         1A         1A
[Pullup]
|Voltage   I(typ)   I(min)   I(max)
-3.3V     100mA      27.1mA     67mA
-1.2V     100mA      27.1mA     67mA
-1.1V     47.4mA     27.1mA     67mA
-700mV    36.43mA    23.9mA     48.76mA
500mV     -22.94mA   -14.36mA   -31.63mA
1.3V      -46.85mA   -27.39mA   -65.63mA
2.1V      -57.1mA    -30.77mA   -82.2mA
3.5V      -61.24mA   -32.7mA    -88.93mA
4.6V      -72.4mA    -57.1mA    -92.26mA
5.5V      -103mA     -66mA      -126.2mA
5.8V      -103mA     -66mA      -139mA
6.6V      -103mA     -66mA      -139mA
[GND_clamp]
|Voltage   I(typ)   I(min)   I(max)
-3.3V     -9.479A    -9.465A    -9.974A
-1.2V     -2.125A    -2.854A    -1.857A
-1.13V    -1.511A    -2.236A    -1.236A
-1.06V    -933.3mA   -1.641A    -660.9mA
-990mV    -433.3mA   -1.082A    -206.9mA
-920mV    -110.3mA   -591mA     -31.45mA
-850mV    -19.78mA   -226.7mA   -13.65mA
-780mV    -8.311mA   -53.93mA   -9.506mA
-710mV    -5.285mA   -11.94mA   -6.262mA
-640mV    -3.232mA   -4.282mA   -3.577mA
3.28V     0A         0A         0A
[POWER_clamp]
|Voltage   I(typ)   I(min)   I(max)
-3.28V    7.329A     6.064A     7.43A
-1.08V    7.329A     6.064A     7.43A
-1.04V    7.329A     6.064A     1.015A
-1V       1.545A     6.064A     138.8mA
-960mV    325.8mA    6.064A     19.13mA
-920mV    68.77mA    1.89A      2.772mA
-880mV    14.59mA    589.1mA    520.3uA
-840mV    3.154mA    183.6mA    196.4uA
-800mV    734.4uA    57.27mA    136.6uA
-720mV    96.98uA    5.605mA    116.7uA
0V        0A         0A         0A
[Ramp]
| variable   typ   min   max
dV/dt_r  1.29633/3.40139n   0.80812/6.55837n   1.59069/2.17401n
dV/dt_f  1.32102/3.36062n   0.74808/6.42861n   1.61073/2.12363n
R_load = 50.000000
[Rising Waveform]
R_fixture= 50.000000
V_fixture= 3.300000
V_fixture_min= 2.700000
V_fixture_max= 3.600000
|time   V(typ)   V(min)   V(max)
0s        1.092V     1.372V     915.6mV
290.3ps   1.092V     1.372V     1.026V
500.5ps   1.1V       1.372V     2.071V
630.6ps   1.213V     1.372V     2.461V
870.9ps   2.148V     1.371V     2.998V
1.191ns   2.785V     1.403V     3.322V
1.361ns   2.964V     1.537V     3.403V
1.782ns   3.141V     2.339V     3.523V
2.072ns   3.196V     2.521V     3.556V
4.985ns   3.3V       2.7V       3.6V
[Rising Waveform]
R_fixture= 50.000000
V_fixture= 0.0
V_fixture_min= 0.0
V_fixture_max= 0.0
|time   V(typ)   V(min)   V(max)
0s        1.083mV    1.044mV    1.187mV
800.8ps   -14.83mV   1.094mV    2.402mV
1.522ns   12.03mV    -11.15mV   246.5mV
2.723ns   256.7mV    3.113mV    1.084V
4.204ns   803.5mV    80.66mV    2.163V
5.526ns   1.342V     199.4mV    2.521V
7.287ns   1.888V     423.7mV    2.608V
9.169ns   2.072V     682.1mV    2.639V
14.25ns   2.151V     1.225V     2.652V
19.94ns   2.161V     1.38V      2.652V
[Falling Waveform]
R_fixture= 50.000000
V_fixture= 3.300000
V_fixture_min= 2.700000
V_fixture_max= 3.600000
|time   V(typ)   V(min)   V(max)
0s        3.3V       2.7V       3.6V
880.9ps   3.315V     2.7V       3.615V
1.481ns   3.311V     2.71V      3.462V
2.563ns   3.193V     2.708V     2.626V
4.204ns   2.533V     2.686V     1.431V
5.285ns   2.055V     2.602V     1.089V
7.167ns   1.445V     2.357V     979.9mV
9.169ns   1.219V     2.066V     944.7mV
13.85ns   1.116V     1.574V     920.3mV
19.94ns   1.092V     1.372V     915.6mV
[Falling Waveform]
R_fixture= 50.000000
V_fixture= 0.0
V_fixture_min= 0.0
V_fixture_max= 0.0
|time   V(typ)   V(min)   V(max)
0s        2.161V     1.38V      2.652V
280.3ps   2.163V     1.38V      2.551V
610.6ps   2.074V     1.38V      1.618V
760.8ps   1.826V     1.381V     1.187V
981ps     1.342V     1.382V     784.2mV
1.271ns   796.2mV    1.327V     480.8mV
1.461ns   577.4mV    1.177V     354.7mV
2.222ns   193.5mV    435.8mV    77.96mV
2.623ns   110.4mV    237.2mV    35.96mV
4.985ns   1.083mV    1.044mV    1.187mV
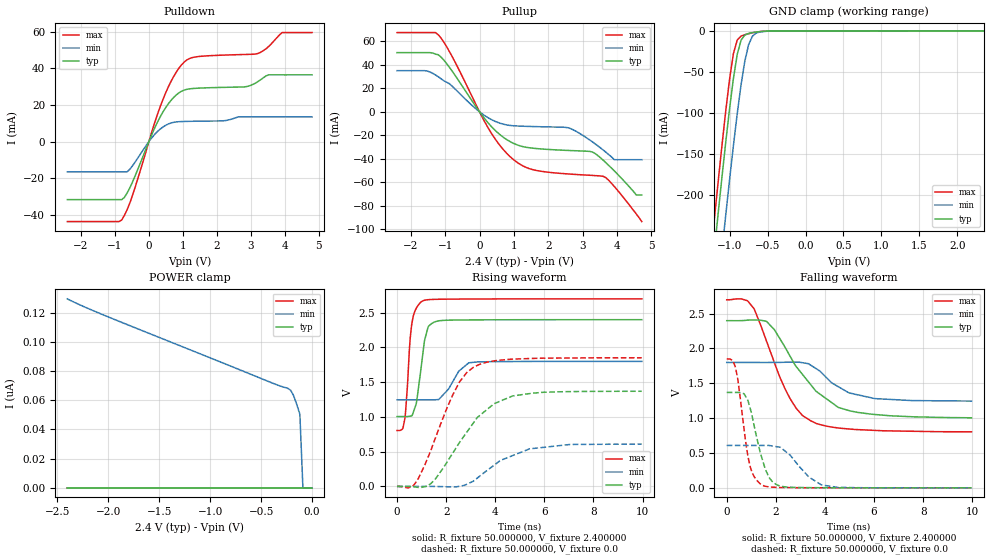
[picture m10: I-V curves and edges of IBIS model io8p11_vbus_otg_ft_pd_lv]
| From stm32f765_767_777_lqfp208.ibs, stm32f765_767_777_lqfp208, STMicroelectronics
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|   Model io8p11_vbus_otg_ft_pd_lv
[Model]  io8p11_vbus_otg_ft_pd_lv
Model_type I/O
Polarity   Non-Inverting
Enable   Active-Low
Vinl =   0.720000V
Vinh =   1.680000V
Vmeas =  1.200000V
Cref =   30.000000pF
Rref =   100.000000M
Vref =   0.0V
C_comp   3.193600pF   3.100000pF   3.332100pF
[Temperature Range]   25.000000   0.125000k   -40.000000
[Pullup Reference]   2.400000V   1.800000V   2.700000V
[Pulldown Reference]   0.0V   0.0V   0.0V
[POWER Clamp Reference]   2.400000V   1.800000V   2.700000V
[GND Clamp Reference]   0.0V   0.0V   0.0V
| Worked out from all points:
|   slope of the pulldown table from 0 to 0.36 V, typ, clamps not added: 25 ohm
|   slope of the pullup table from 0 to 0.36 V, typ, clamps not added: 27.7 ohm
|   GND clamp passes 1 mA (typ) near -0.61 V on its own axis
|   rising waveform, R_fixture 50.000000, V_fixture 2.400000: 20-80 % time 313ps typ, 638ps min, 225ps max; typ from 1 V to 2.4 V
|   rising waveform, R_fixture 50.000000, V_fixture 0.0: 20-80 % time 1.73ns typ, 1.74ns min, 1.31ns max; typ from 0 V to 1.37 V
|   falling waveform, R_fixture 50.000000, V_fixture 2.400000: 20-80 % time 1.84ns typ, 1.32ns min, 1.36ns max; typ from 2.4 V to 1 V
|   falling waveform, R_fixture 50.000000, V_fixture 0.0: 20-80 % time 575ps typ, 975ps min, 434ps max; typ from 1.37 V to 0 V
[Pulldown]
|Voltage   I(typ)   I(min)   I(max)
-2.4V     -31.69mA   -16.5mA    -43.66mA
-800mV    -31.69mA   -16.5mA    -42.82mA
-480mV    -21.96mA   -13.17mA   -29.19mA
80mV      3.63mA     1.966mA    5.014mA
480mV     18.15mA    8.738mA    26.02mA
800mV     25.38mA    10.72mA    37.77mA
1.12V     28.53mA    11.02mA    44.6mA
2.8V      29.84mA    13.49mA    47.53mA
3.2V      32.65mA    13.49mA    48.04mA
3.52V     36.42mA    13.49mA    51.83mA
3.92V     36.42mA    13.49mA    59.49mA
4.8V      36.42mA    13.49mA    59.49mA
[Pullup]
|Voltage   I(typ)   I(min)   I(max)
-2.4V     50.45mA    35.08mA    67.53mA
-1.52V    50.45mA    34.74mA    67.53mA
-1.2V     48.64mA    29.87mA    65.68mA
320mV     -11.75mA   -6.207mA   -17.08mA
1.04V     -27.53mA   -11.97mA   -41.91mA
1.6V      -31.13mA   -12.58mA   -49.63mA
2.56V     -32.88mA   -13.49mA   -52.9mA
3.28V     -34.19mA   -25.53mA   -54.18mA
3.6V      -41.31mA   -32.62mA   -54.99mA
3.92V     -50.33mA   -40.8mA    -63.62mA
4.56V     -70.9mA    -40.8mA    -87.08mA
4.72V     -70.9mA    -40.8mA    -93.5mA
[GND_clamp]
|Voltage   I(typ)   I(min)   I(max)
-2.4V     -1.424A    -1.508A    -1.393A
-1.25V    -311.3mA   -401.9mA   -273.4mA
-1.2V     -265.5mA   -356.1mA   -227.3mA
-1.15V    -220.5mA   -310.9mA   -182mA
-1.1V     -176.4mA   -266.2mA   -138mA
-1.05V    -133.9mA   -222.5mA   -96.06mA
-950mV    -57.51mA   -139mA     -27.36mA
-900mV    -28.55mA   -100.5mA   -11.04mA
-850mV    -11.34mA   -65.68mA   -6.337mA
-750mV    -3.08mA    -16.7mA    -3.439mA
-600mV    -875.9uA   -1.303mA   -865.8uA
2.35V     58.09uA    37.92uA    67.25uA
[POWER_clamp]
|Voltage   I(typ)   I(min)   I(max)
-2.4V     0A         129.4nA    0A
-1.98V    0A         116.5nA    0A
-390mV    0A         71.78nA    0A
-240mV    0A         68.22nA    0A
-210mV    0A         66.81nA    0A
-180mV    0A         62.95nA    0A
-120mV    0A         50.47nA    0A
-90mV     0A         0A         0A
0V        0A         0A         0A
[Ramp]
| variable   typ   min   max
dV/dt_r  0.82110/1.72620n   0.36439/1.73905n   1.11042/1.30587n
dV/dt_f  0.83268/1.83184n   0.33276/1.34137n   1.13553/1.35723n
R_load = 50.000000
[Rising Waveform]
R_fixture= 50.000000
V_fixture= 2.400000
V_fixture_min= 1.800000
V_fixture_max= 2.700000
|time   V(typ)   V(min)   V(max)
0s        1.005V     1.245V     804.2mV
320.3ps   1.005V     1.246V     976.2mV
540.5ps   1.012V     1.246V     2.145V
620.6ps   1.024V     1.246V     2.374V
800.8ps   1.224V     1.246V     2.574V
1.041ns   1.879V     1.245V     2.668V
1.281ns   2.304V     1.245V     2.687V
1.702ns   2.382V     1.251V     2.693V
2.923ns   2.396V     1.779V     2.696V
9.97ns    2.399V     1.799V     2.698V
[Rising Waveform]
R_fixture= 50.000000
V_fixture= 0.0
V_fixture_min= 0.0
V_fixture_max= 0.0
|time   V(typ)   V(min)   V(max)
0s        171uV      66.49uV    495.2uV
560.6ps   -1.97mV    49.08uV    -9.889mV
840.8ps   -12.99mV   52.81uV    94.03mV
1.361ns   34.86mV    86.09uV    504.6mV
2.282ns   486.5mV    -7.374mV   1.325V
2.563ns   642mV      3.668mV    1.512V
3.123ns   919.7mV    79.2mV     1.716V
3.964ns   1.191V     308.4mV    1.806V
5.405ns   1.336V     540.6mV    1.84V
9.97ns    1.369V     608.3mV    1.851V
[Falling Waveform]
R_fixture= 50.000000
V_fixture= 2.400000
V_fixture_min= 1.800000
V_fixture_max= 2.700000
|time   V(typ)   V(min)   V(max)
0s        2.399V     1.799V     2.698V
680.7ps   2.401V     1.799V     2.703V
1.101ns   2.409V     1.799V     2.576V
1.622ns   2.388V     1.799V     2.105V
2.382ns   2.013V     1.802V     1.416V
2.843ns   1.735V     1.804V     1.136V
3.423ns   1.48V      1.76V      962.3mV
4.545ns   1.154V     1.452V     859.4mV
4.985ns   1.109V     1.362V     844.6mV
9.97ns    1.005V     1.245V     804.2mV
[Falling Waveform]
R_fixture= 50.000000
V_fixture= 0.0
V_fixture_min= 0.0
V_fixture_max= 0.0
|time   V(typ)   V(min)   V(max)
0s        1.369V     608.3mV    1.851V
240.2ps   1.369V     608.4mV    1.83V
360.4ps   1.369V     608.4mV    1.722V
860.9ps   1.255V     608.2mV    457.3mV
1.041ns   1.019V     608mV      213.3mV
1.441ns   417.8mV    608.3mV    39.33mV
1.722ns   152.3mV    608.2mV    13.54mV
2.042ns   43.9mV     590.4mV    6.857mV
3.864ns   2.004mV    41.68mV    1.25mV
9.97ns    171uV      66.49uV    495.2uV
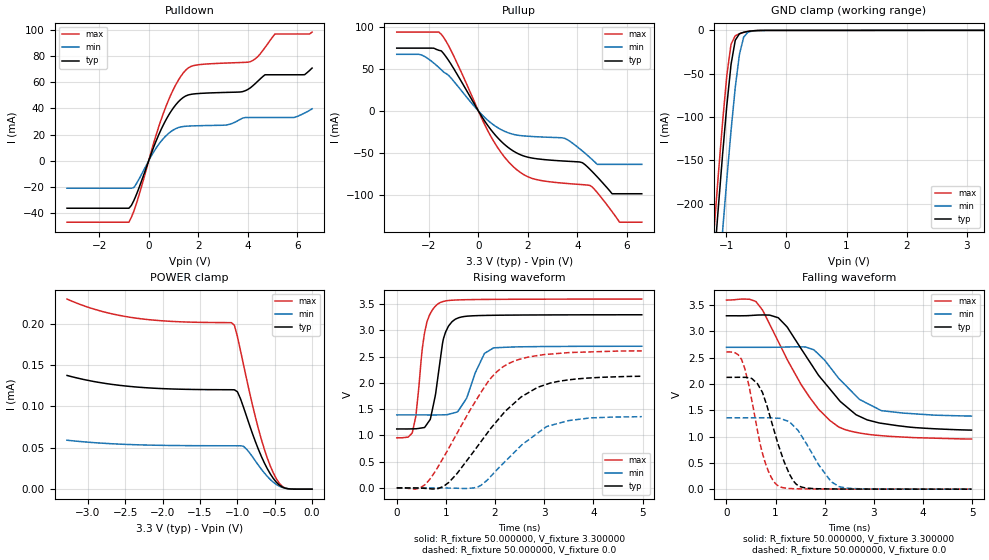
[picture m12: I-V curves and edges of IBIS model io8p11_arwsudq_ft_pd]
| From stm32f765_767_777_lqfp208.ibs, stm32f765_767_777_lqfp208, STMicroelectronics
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|   Model io8p11_arwsudq_ft_pd
[Model]  io8p11_arwsudq_ft_pd
Model_type I/O
Polarity   Non-Inverting
Enable   Active-Low
Vinl =   0.990000V
Vinh =   2.310000V
Vmeas =  1.650000V
Cref =   30.000000pF
Rref =   100.000000M
Vref =   0.0V
C_comp   2.905500pF   2.831700pF   2.987900pF
[Temperature Range]   25.000000   0.125000k   -40.000000
[Pullup Reference]   3.300000V   2.700000V   3.600000V
[Pulldown Reference]   0.0V   0.0V   0.0V
[POWER Clamp Reference]   3.300000V   2.700000V   3.600000V
[GND Clamp Reference]   0.0V   0.0V   0.0V
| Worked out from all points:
|   slope of the pulldown table from 0 to 0.495 V, typ, clamps not added: 20.9 ohm
|   slope of the pullup table from 0 to 0.495 V, typ, clamps not added: 22.6 ohm
|   GND clamp passes 1 mA (typ) near -0.62 V on its own axis
|   rising waveform, R_fixture 50.000000, V_fixture 3.300000: 20-80 % time 218ps typ, 339ps min, 191ps max; typ from 1.12 V to 3.3 V
|   rising waveform, R_fixture 50.000000, V_fixture 0.0: 20-80 % time 1.14ns typ, 963ps min, 998ps max; typ from 0 V to 2.13 V
|   falling waveform, R_fixture 50.000000, V_fixture 3.300000: 20-80 % time 1.07ns typ, 809ps min, 998ps max; typ from 3.3 V to 1.12 V
|   falling waveform, R_fixture 50.000000, V_fixture 0.0: 20-80 % time 435ps typ, 549ps min, 356ps max; typ from 2.13 V to 0 V
[Pulldown]
|Voltage   I(typ)   I(min)   I(max)
-3.3V     -36.4mA    -21.07mA   -47.09mA
-800mV    -36.4mA    -21.07mA   -47.09mA
-600mV    -30.5mA    -20.54mA   -38.69mA
700mV     31.4mA     19.11mA    41.71mA
1.2V      45.15mA    25.37mA    61.75mA
1.6V      50.35mA    26.5mA     71.06mA
3.1V      52.27mA    27.26mA    74.75mA
4.1V      55.71mA    33.04mA    75.8mA
4.7V      65.8mA     33.04mA    86.69mA
5.1V      65.8mA     33.04mA    97.03mA
6.3V      65.87mA    36.5mA     97.03mA
6.6V      70.92mA    39.71mA    98.48mA
[Pullup]
|Voltage   I(typ)   I(min)   I(max)
-3.3V     74.74mA    67.41mA    93.79mA
-2.3V     74.74mA    66.57mA    93.79mA
-1.5V     71.47mA    49mA       91.17mA
500mV     -22.07mA   -14mA      -30.03mA
1.6V      -50.64mA   -28.81mA   -70.96mA
3.5V      -59.53mA   -32.66mA   -85.92mA
4.2V      -61.44mA   -47.48mA   -87.46mA
4.5V      -69.08mA   -55.13mA   -88.39mA
4.8V      -78.24mA   -63.4mA    -96.88mA
5.4V      -98.3mA    -63.4mA    -119.6mA
5.7V      -98.3mA    -63.4mA    -132.1mA
6.6V      -98.3mA    -63.4mA    -132.1mA
[GND_clamp]
|Voltage   I(typ)   I(min)   I(max)
-3.3V     -2.316A    -2.395A    -2.288A
-1.2V     -266mA     -356.3mA   -228.4mA
-1.13V    -203.2mA   -293mA     -165.3mA
-1.06V    -142.7mA   -231.3mA   -105.2mA
-990mV    -86.51mA   -171.7mA   -51.78mA
-920mV    -39.3mA    -115.7mA   -15.95mA
-850mV    -11.38mA   -65.76mA   -6.112mA
-780mV    -3.842mA   -27.55mA   -3.895mA
-710mV    -2.102mA   -7.755mA   -2.396mA
-640mV    -1.159mA   -2.138mA   -1.234mA
-570mV    -535.1uA   -809uA     -490.4uA
3.28V     81.28uA    57.87uA    93.98uA
[POWER_clamp]
|Voltage   I(typ)   I(min)   I(max)
-3.28V    137.3uA    59.14uA    229.6uA
-2.36V    123.4uA    53.65uA    206.6uA
-1.08V    120.1uA    52.41uA    201.1uA
-1.04V    120uA      52.41uA    198uA
-1V       117.7uA    52.4uA     184.5uA
-920mV    99.46uA    51.91uA    151.2uA
-720mV    48.42uA    29.12uA    73.51uA
-600mV    24.82uA    15.47uA    37.72uA
-520mV    13.1uA     8.45uA     19.84uA
-440mV    5.058uA    3.61uA     7.276uA
-360mV    1.193uA    1.129uA    1.311uA
0V        0A         0A         0A
[Ramp]
| variable   typ   min   max
dV/dt_r  1.25970/1.13281n   0.80340/0.95414n   1.55957/0.99546n
dV/dt_f  1.27548/1.04691n   0.76788/0.78216n   1.56910/0.99071n
R_load = 50.000000
[Rising Waveform]
R_fixture= 50.000000
V_fixture= 3.300000
V_fixture_min= 2.700000
V_fixture_max= 3.600000
|time   V(typ)   V(min)   V(max)
0s        1.123V     1.391V     953.9mV
320.3ps   1.125V     1.391V     1.067V
390.4ps   1.127V     1.391V     1.376V
570.6ps   1.157V     1.391V     2.974V
690.7ps   1.339V     1.39V      3.336V
870.9ps   2.343V     1.392V     3.525V
961ps     2.875V     1.393V     3.556V
1.131ns   3.172V     1.422V     3.576V
1.972ns   3.289V     2.669V     3.592V
4.985ns   3.299V     2.699V     3.598V
[Rising Waveform]
R_fixture= 50.000000
V_fixture= 0.0
V_fixture_min= 0.0
V_fixture_max= 0.0
|time   V(typ)   V(min)   V(max)
0s        350.1uV    197.3uV    636.1uV
480.5ps   -3.156mV   140.7uV    1.812mV
670.7ps   -15.44mV   180.7uV    162.6mV
961ps     36.4mV     -1.108mV   596.4mV
1.662ns   816.2mV    23.19mV    1.742V
1.932ns   1.157V     239.5mV    2.111V
2.242ns   1.491V     538.8mV    2.353V
3.053ns   1.976V     1.171V     2.544V
3.934ns   2.095V     1.333V     2.591V
4.985ns   2.127V     1.357V     2.611V
[Falling Waveform]
R_fixture= 50.000000
V_fixture= 3.300000
V_fixture_min= 2.700000
V_fixture_max= 3.600000
|time   V(typ)   V(min)   V(max)
0s        3.299V     2.699V     3.598V
600.6ps   3.31V      2.699V     3.568V
740.7ps   3.314V     2.699V     3.396V
1.051ns   3.262V     2.7V       2.815V
1.512ns   2.683V     2.707V     2.003V
1.782ns   2.297V     2.649V     1.636V
2.282ns   1.705V     2.11V      1.184V
2.643ns   1.413V     1.768V     1.08V
3.153ns   1.253V     1.494V     1.018V
4.985ns   1.123V     1.391V     953.9mV
[Falling Waveform]
R_fixture= 50.000000
V_fixture= 0.0
V_fixture_min= 0.0
V_fixture_max= 0.0
|time   V(typ)   V(min)   V(max)
0s        2.127V     1.357V     2.611V
310.3ps   2.128V     1.357V     2.462V
460.5ps   2.116V     1.357V     1.958V
630.6ps   2.006V     1.357V     1.116V
850.9ps   1.499V     1.359V     344.2mV
1.061ns   827mV      1.349V     58.77mV
1.421ns   93.48mV    1.151V     7.635mV
1.882ns   7.615mV    455.1mV    3.277mV
2.292ns   3.253mV    47.99mV    2.244mV
4.985ns   350.1uV    197.3uV    636.1uV
